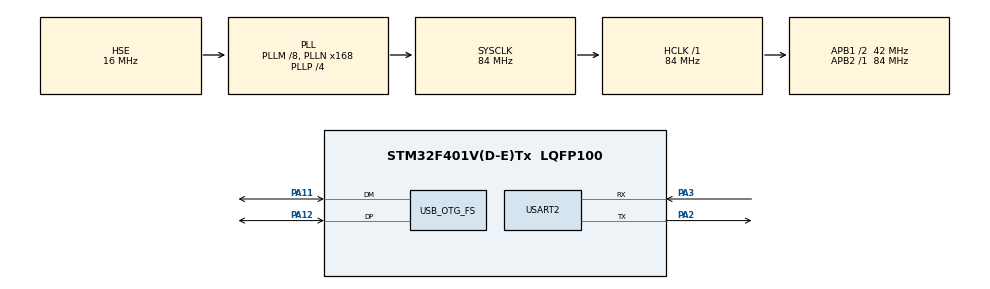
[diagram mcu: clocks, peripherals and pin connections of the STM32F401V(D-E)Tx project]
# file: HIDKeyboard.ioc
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Mcu.Family=STM32F4
Mcu.Name=STM32F401V(D-E)Tx
Mcu.Package=LQFP100
NVIC.OTG_FS_IRQn=true\:0\:0\:false\:false\:true\:false\:true
NVIC.PriorityGroup=NVIC_PRIORITYGROUP_4
PA11.Mode=Device_Only
PA11.Signal=USB_OTG_FS_DM
PA12.Mode=Device_Only
PA12.Signal=USB_OTG_FS_DP
PA2.Mode=Asynchronous
PA2.Signal=USART2_TX
PA3.Mode=Asynchronous
PA3.Signal=USART2_RX
PH0\ -\ OSC_IN.Mode=HSE-External-Oscillator
PH0\ -\ OSC_IN.Signal=RCC_OSC_IN
PH1\ -\ OSC_OUT.Mode=HSE-External-Oscillator
PH1\ -\ OSC_OUT.Signal=RCC_OSC_OUT
ProjectManager.HeapSize=0x400
ProjectManager.StackSize=0x600
ProjectManager.TargetToolchain=SW4STM32
RCC.48MHZClocksFreq_Value=48000000
RCC.AHBFreq_Value=84000000
RCC.APB1CLKDivider=RCC_HCLK_DIV2
RCC.APB1Freq_Value=42000000
RCC.APB1TimFreq_Value=84000000
RCC.APB2Freq_Value=84000000
RCC.APB2TimFreq_Value=84000000
RCC.CortexFreq_Value=84000000
RCC.HCLKFreq_Value=84000000
RCC.HSE_VALUE=16000000
RCC.HSI_VALUE=16000000
RCC.LSE_VALUE=32768
RCC.PLLM=8
RCC.PLLN=168
RCC.PLLP=RCC_PLLP_DIV4
RCC.PLLQ=7
RCC.SYSCLKFreq_VALUE=84000000
RCC.SYSCLKSource=RCC_SYSCLKSOURCE_PLLCLK
RCC.VCOOutputFreq_Value=336000000
USART2.VirtualMode=VM_ASYNC
USB_DEVICE.CLASS_NAME_FS=HID
USB_DEVICE.MANUFACTURER_STRING-HID_FS=Apple Inc.
USB_DEVICE.PID_HID_FS=0x0250
USB_DEVICE.PRODUCT_STRING_HID_FS=Apple Keyboard
USB_DEVICE.USBD_MAX_NUM_INTERFACES-HID_FS=2
USB_DEVICE.USBD_SELF_POWERED-HID_FS=0
USB_DEVICE.VID-HID_FS=0x05ac
USB_DEVICE.VirtualMode-HID_FS=Hid
USB_DEVICE.VirtualModeFS=Hid_FS
USB_OTG_FS.VirtualMode=Device_Only
VP_USB_DEVICE_VS_USB_DEVICE_HID_FS.Mode=HID_FS
board=custom

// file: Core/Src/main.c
/* USER CODE BEGIN Header */
/**
  ******************************************************************************
  * @file           : main.c
  * @brief          : Main program body
  ******************************************************************************
  * @attention
  *
  * <h2><center>&copy; Copyright (c) 2019 STMicroelectronics.
  * All rights reserved.</center></h2>
  *
  * This software component is licensed by ST under Ultimate Liberty license
  * SLA0044, the "License"; You may not use this file except in compliance with
  * the License. You may obtain a copy of the License at:
  *                             www.st.com/SLA0044
  *
  ******************************************************************************
  */
/* USER CODE END Header */

#include "main.h"
#include "usb_device.h"
#include "usbd_hid.h"

UART_HandleTypeDef huart2;

void SystemClock_Config(void);
static void MX_GPIO_Init(void);
static void MX_USART2_UART_Init(void);

/* USER CODE BEGIN 0 */
void sendHIDReport(int keyCode, int status);
/* USER CODE END 0 */

int main(void)
{

  /* MCU Configuration--------------------------------------------------------*/

  /* Reset of all peripherals, Initializes the Flash interface and the Systick. */
  HAL_Init();

  /* Configure the system clock */
  SystemClock_Config();

  /* Initialize all configured peripherals */
  MX_GPIO_Init();

  // pulls USB D+ high on steval-mki109v3 board
  HAL_GPIO_WritePin(GPIOA, GPIO_PIN_9, GPIO_PIN_RESET);

  MX_USART2_UART_Init();
  MX_USB_DEVICE_Init();

  /* Infinite loop */
  /* USER CODE BEGIN WHILE */

  // Button states
  int button1 = 0;
  int button2 = 0;

  while (1)
  {
	  __WFI();

	// Only poll buttons if we can send a report, this way we don't miss very fast
	// button presses where both press and release happens in the same hid poll
	extern USBD_HandleTypeDef hUsbDeviceFS;
	if(((USBD_HID_HandleTypeDef *)hUsbDeviceFS.pClassData)->state != HID_IDLE) continue;

	// check the buttons and send report
	int b = HAL_GPIO_ReadPin(GPIOA, GPIO_PIN_10);
	if(b != button1) {
		button1 = b;
		sendHIDReport(0x3A, b); // brightness down
	} else {
		b = HAL_GPIO_ReadPin(GPIOB, GPIO_PIN_10);
		if(b != button2) {
			button2 = b;
			sendHIDReport(0x3B, b); // brightness up
		}
	}

  }
}

typedef union {
    struct {
	uint8_t meta; // control keys and modifiers flags
	uint8_t reserved; // not used
	uint8_t keys[5]; // keycodes
	uint8_t vendor; // unknown
    } f;
    uint8_t data[8];
} KeyboardReport_t;

static KeyboardReport_t sHIDReport;
void sendHIDReport(int keyCode, int status)
{
	extern USBD_HandleTypeDef hUsbDeviceFS;
	sHIDReport.f.keys[0] = status ? keyCode : 0;
	USBD_HID_SendReport(&hUsbDeviceFS, sHIDReport.data, 8);
}

void SystemClock_Config(void)
{
  RCC_OscInitTypeDef RCC_OscInitStruct = {0};
  RCC_ClkInitTypeDef RCC_ClkInitStruct = {0};

  /** Configure the main internal regulator output voltage
  */
  __HAL_RCC_PWR_CLK_ENABLE();
  __HAL_PWR_VOLTAGESCALING_CONFIG(PWR_REGULATOR_VOLTAGE_SCALE2);
  /** Initializes the CPU, AHB and APB busses clocks
  */
  RCC_OscInitStruct.OscillatorType = RCC_OSCILLATORTYPE_HSE;
  RCC_OscInitStruct.HSEState = RCC_HSE_ON;
  RCC_OscInitStruct.PLL.PLLState = RCC_PLL_ON;
  RCC_OscInitStruct.PLL.PLLSource = RCC_PLLSOURCE_HSE;
  RCC_OscInitStruct.PLL.PLLM = 8;
  RCC_OscInitStruct.PLL.PLLN = 168;
  RCC_OscInitStruct.PLL.PLLP = RCC_PLLP_DIV4;
  RCC_OscInitStruct.PLL.PLLQ = 7;
  if (HAL_RCC_OscConfig(&RCC_OscInitStruct) != HAL_OK)
  {
    Error_Handler();
  }
  /** Initializes the CPU, AHB and APB busses clocks
  */
  RCC_ClkInitStruct.ClockType = RCC_CLOCKTYPE_HCLK|RCC_CLOCKTYPE_SYSCLK
                              |RCC_CLOCKTYPE_PCLK1|RCC_CLOCKTYPE_PCLK2;
  RCC_ClkInitStruct.SYSCLKSource = RCC_SYSCLKSOURCE_PLLCLK;
  RCC_ClkInitStruct.AHBCLKDivider = RCC_SYSCLK_DIV1;
  RCC_ClkInitStruct.APB1CLKDivider = RCC_HCLK_DIV2;
  RCC_ClkInitStruct.APB2CLKDivider = RCC_HCLK_DIV1;

  if (HAL_RCC_ClockConfig(&RCC_ClkInitStruct, FLASH_LATENCY_2) != HAL_OK)
  {
    Error_Handler();
  }
}

static void MX_USART2_UART_Init(void)
{

  huart2.Instance = USART2;
  huart2.Init.BaudRate = 115200;
  huart2.Init.WordLength = UART_WORDLENGTH_8B;
  huart2.Init.StopBits = UART_STOPBITS_1;
  huart2.Init.Parity = UART_PARITY_NONE;
  huart2.Init.Mode = UART_MODE_TX_RX;
  huart2.Init.HwFlowCtl = UART_HWCONTROL_NONE;
  huart2.Init.OverSampling = UART_OVERSAMPLING_16;
  if (HAL_UART_Init(&huart2) != HAL_OK)
  {
    Error_Handler();
  }

}

static void MX_GPIO_Init(void)
{
	GPIO_InitTypeDef GPIO_InitStruct = {0};

  /* GPIO Ports Clock Enable */
  __HAL_RCC_GPIOH_CLK_ENABLE();
  __HAL_RCC_GPIOA_CLK_ENABLE();
  __HAL_RCC_GPIOB_CLK_ENABLE();

  // Button #1 (SW1)
  GPIO_InitStruct.Pin = GPIO_PIN_10;
  GPIO_InitStruct.Mode = GPIO_MODE_INPUT;
  GPIO_InitStruct.Pull = GPIO_NOPULL;
  HAL_GPIO_Init(GPIOA, &GPIO_InitStruct);

  // Button #2 (SW2)
  GPIO_InitStruct.Pin = GPIO_PIN_10;
  GPIO_InitStruct.Mode = GPIO_MODE_INPUT;
  GPIO_InitStruct.Pull = GPIO_NOPULL;
  HAL_GPIO_Init(GPIOB, &GPIO_InitStruct);
}

void Error_Handler(void)
{
}

/************************ (C) COPYRIGHT STMicroelectronics *****END OF FILE****/
